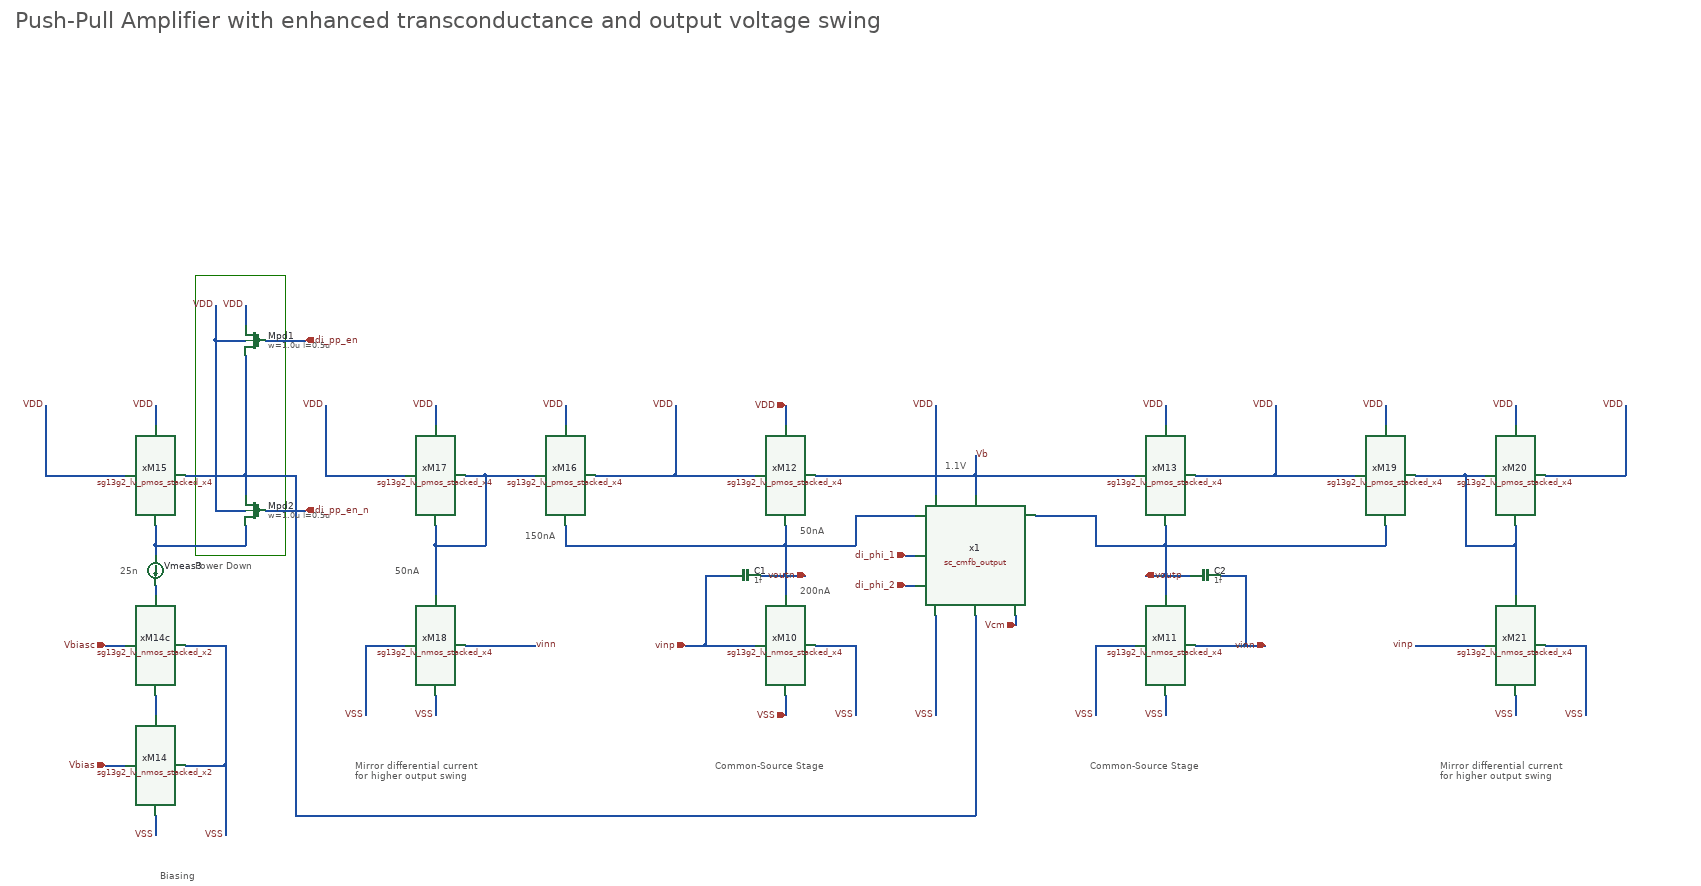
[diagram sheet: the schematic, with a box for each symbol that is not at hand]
v {xschem version=3.4.7 file_version=1.2}
G {}
K {}
V {}
S {}
E {}
P 4 5 540 -1280 540 -1840 720 -1840 720 -1280 540 -1280 {dash = 8}
T {Push-Pull Amplifier with enhanced transconductance and output voltage swing} 180 -2360 0 0 1.5 1.5 {}
T {200nA} 1750 -1220 0 0 0.4 0.4 {}
T {Common-Source Stage} 1580 -870 0 0 0.5 0.5 {}
T {Common-Source Stage} 2330 -870 0 0 0.5 0.5 {}
T {Mirror differential current
for higher output swing} 860 -870 0 0 0.5 0.5 {}
T {Mirror differential current
for higher output swing} 3030 -870 0 0 0.5 0.5 {}
T {50nA} 940 -1260 0 0 0.4 0.4 {}
T {150nA} 1200 -1330 0 0 0.4 0.4 {}
T {50nA} 1750 -1340 0 0 0.4 0.4 {}
T {25n} 390 -1260 0 0 0.4 0.4 {}
T {Power Down} 540 -1270 0 0 0.4 0.4 {}
T {Biasing} 470 -650 0 0 0.5 0.5 {}
T {1.1V} 2040 -1470 0 0 0.4 0.4 {}
N 1720 -1580 1720 -1540 {lab=VDD}
N 1860 -1100 1860 -960 {lab=VSS}
N 2640 -1100 2680 -1100 {lab=vinn}
N 2480 -1580 2480 -1540 {lab=VDD}
N 2540 -1100 2640 -1100 {lab=vinn}
N 2340 -1100 2340 -960 {lab=VSS}
N 2480 -1240 2480 -1200 {lab=voutp}
N 1500 -1580 1500 -1440 {lab=VDD}
N 2700 -1580 2700 -1440 {lab=VDD}
N 1500 -1440 1660 -1440 {lab=VDD}
N 2540 -1440 2700 -1440 {lab=VDD}
N 2480 -1300 2480 -1240 {lab=voutp}
N 1340 -1440 1500 -1440 {lab=VDD}
N 2480 -1340 2480 -1300 {lab=voutp}
N 1280 -1580 1280 -1540 {lab=VDD}
N 800 -1440 960 -1440 {lab=VDD}
N 1020 -1580 1020 -1540 {lab=VDD}
N 1080 -1100 1220 -1100 {lab=vinn}
N 1020 -1000 1020 -960 {lab=VSS}
N 1780 -1100 1860 -1100 {lab=VSS}
N 1720 -1000 1720 -960 {lab=VSS}
N 1560 -1100 1660 -1100 {lab=vinp}
N 2480 -1000 2480 -960 {lab=VSS}
N 2340 -1100 2420 -1100 {lab=VSS}
N 2640 -1240 2640 -1100 {lab=vinn}
N 1280 -1340 1280 -1300 {lab=voutn}
N 1720 -1340 1720 -1300 {lab=voutn}
N 2590 -1240 2640 -1240 {lab=vinn}
N 2480 -1240 2530 -1240 {lab=voutp}
N 1670 -1240 1720 -1240 {lab=voutn}
N 1560 -1240 1610 -1240 {lab=vinp}
N 1560 -1240 1560 -1100 {lab=vinp}
N 1520 -1100 1560 -1100 {lab=vinp}
N 1720 -1240 1720 -1200 {lab=voutn}
N 1120 -1440 1220 -1440 {lab=#net1}
N 1020 -1300 1120 -1300 {lab=#net1}
N 1020 -1340 1020 -1300 {lab=#net1}
N 1120 -1440 1120 -1300 {lab=#net1}
N 1080 -1440 1120 -1440 {lab=#net1}
N 2920 -1580 2920 -1540 {lab=VDD}
N 3240 -1440 3400 -1440 {lab=VDD}
N 3400 -1580 3400 -1440 {lab=VDD}
N 3180 -1580 3180 -1540 {lab=VDD}
N 2980 -1100 3120 -1100 {lab=vinp}
N 3180 -1300 3180 -1200 {lab=#net2}
N 3240 -1100 3320 -1100 {lab=VSS}
N 3320 -1100 3320 -960 {lab=VSS}
N 3180 -1000 3180 -960 {lab=VSS}
N 2920 -1340 2920 -1300 {lab=voutp}
N 2980 -1440 3080 -1440 {lab=#net2}
N 3080 -1300 3180 -1300 {lab=#net2}
N 3180 -1340 3180 -1300 {lab=#net2}
N 3080 -1440 3080 -1300 {lab=#net2}
N 3080 -1440 3120 -1440 {lab=#net2}
N 2700 -1440 2860 -1440 {lab=VDD}
N 1020 -1300 1020 -1200 {lab=#net1}
N 2480 -1300 2920 -1300 {lab=voutp}
N 1720 -1300 1860 -1300 {lab=voutn}
N 2340 -1300 2480 -1300 {lab=voutp}
N 2440 -1240 2480 -1240 {lab=voutp}
N 1720 -1240 1760 -1240 {lab=voutn}
N 1280 -1300 1720 -1300 {lab=voutn}
N 2100 -1440 2420 -1440 {lab=Vb}
N 2020 -1580 2020 -1400 {lab=VDD}
N 2100 -1440 2100 -1400 {lab=Vb}
N 1780 -1440 2100 -1440 {lab=Vb}
N 1860 -1360 1980 -1360 {lab=voutn}
N 1860 -1360 1860 -1300 {lab=voutn}
N 2220 -1360 2340 -1360 {lab=voutp}
N 2340 -1360 2340 -1300 {lab=voutp}
N 2100 -1160 2100 -760 {lab=#net3}
N 2020 -1160 2020 -960 {lab=VSS}
N 1960 -1280 1980 -1280 {lab=di_phi_1}
N 1960 -1220 1980 -1220 {lab=di_phi_2}
N 2180 -1160 2180 -1140 {lab=Vcm}
N 1720 -1300 1720 -1240 {lab=voutn}
N 2100 -1480 2100 -1440 {lab=Vb}
N 240 -1580 240 -1440 {lab=VDD}
N 240 -1440 400 -1440 {lab=VDD}
N 460 -1580 460 -1540 {lab=VDD}
N 460 -1300 460 -1280 {lab=#net4}
N 460 -1220 460 -1200 {lab=#net5}
N 880 -1100 880 -960 {lab=VSS}
N 640 -1780 640 -1740 {lab=VDD}
N 640 -1440 640 -1400 {lab=#net3}
N 640 -1340 640 -1300 {lab=#net4}
N 520 -1440 640 -1440 {lab=#net3}
N 640 -1680 640 -1440 {lab=#net3}
N 680 -1710 760 -1710 {lab=di_pp_en}
N 680 -1370 760 -1370 {lab=di_pp_en_n}
N 580 -1710 580 -1370 {lab=VDD}
N 580 -1370 640 -1370 {lab=VDD}
N 580 -1710 640 -1710 {lab=VDD}
N 580 -1780 580 -1710 {lab=VDD}
N 800 -1580 800 -1440 {lab=VDD}
N 460 -1300 640 -1300 {lab=#net4}
N 460 -1340 460 -1300 {lab=#net4}
N 640 -1440 740 -1440 {lab=#net3}
N 740 -1440 740 -760 {lab=#net3}
N 880 -1100 960 -1100 {lab=VSS}
N 740 -760 2100 -760 {lab=#net3}
N 520 -1100 600 -1100 {lab=VSS}
N 600 -860 600 -720 {lab=VSS}
N 460 -1000 460 -960 {lab=#net4}
N 460 -760 460 -720 {lab=VSS}
N 520 -860 600 -860 {lab=VSS}
N 600 -1100 600 -860 {lab=VSS}
N 360 -1100 400 -1100 {lab=Vbiasc}
N 360 -860 400 -860 {lab=Vbias}
C {title-2.sym} 0 0 0 0 {name=l2 author="Simon Dorrer" rev=1.0 lock=true}
C {stacked_transistors/sg13g2_lv_pmos_stacked/sg13g2_lv_pmos_stacked_x4.sym} 1720 -1440 0 1 {name=xM12 W_P=4.0u L_P=40.0u NG_P=8 M_P=1}
C {stacked_transistors/sg13g2_lv_nmos_stacked/sg13g2_lv_nmos_stacked_x4.sym} 1720 -1100 0 0 {name=xM10 W_N=2.0u L_N=40.0u NG_N=4 M_N=1}
C {ipin.sym} 1520 -1100 0 0 {name=p4 lab=vinp}
C {ipin.sym} 2680 -1100 2 0 {name=p6 lab=vinn}
C {opin.sym} 2440 -1240 2 0 {name=p3 lab=voutp}
C {opin.sym} 1760 -1240 2 1 {name=p7 lab=voutn}
C {devices/iopin.sym} 1720 -1580 3 0 {name=p34 lab=VDD}
C {devices/iopin.sym} 1720 -960 1 0 {name=p1 lab=VSS}
C {lab_pin.sym} 1860 -960 3 0 {name=p36 sig_type=std_logic lab=VSS}
C {lab_pin.sym} 2340 -960 1 1 {name=p12 sig_type=std_logic lab=VSS}
C {lab_pin.sym} 2480 -1580 3 1 {name=p5 sig_type=std_logic lab=VDD}
C {lab_pin.sym} 2480 -960 1 1 {name=p8 sig_type=std_logic lab=VSS}
C {stacked_transistors/sg13g2_lv_pmos_stacked/sg13g2_lv_pmos_stacked_x4.sym} 2480 -1440 0 0 {name=xM13 W_P=4.0u L_P=40.0u NG_P=8 M_P=1}
C {stacked_transistors/sg13g2_lv_nmos_stacked/sg13g2_lv_nmos_stacked_x4.sym} 2480 -1100 0 1 {name=xM11 W_N=2.0u L_N=40.0u NG_N=4 M_N=1}
C {lab_pin.sym} 2700 -1580 3 1 {name=p9 sig_type=std_logic lab=VDD}
C {stacked_transistors/sg13g2_lv_pmos_stacked/sg13g2_lv_pmos_stacked_x4.sym} 1280 -1440 0 0 {name=xM16 W_P=3.0u L_P=40.0u NG_P=6 M_P=1}
C {lab_pin.sym} 1280 -1580 3 1 {name=p15 sig_type=std_logic lab=VDD}
C {lab_pin.sym} 1500 -1580 3 1 {name=p10 sig_type=std_logic lab=VDD}
C {stacked_transistors/sg13g2_lv_pmos_stacked/sg13g2_lv_pmos_stacked_x4.sym} 1020 -1440 0 1 {name=xM17 W_P=1.0u L_P=40.0u NG_P=2 M_P=1}
C {stacked_transistors/sg13g2_lv_nmos_stacked/sg13g2_lv_nmos_stacked_x4.sym} 1020 -1100 0 1 {name=xM18 W_N=0.5u L_N=40.0u NG_N=1 M_N=1}
C {lab_pin.sym} 1020 -1580 3 1 {name=p16 sig_type=std_logic lab=VDD}
C {lab_pin.sym} 1020 -960 3 0 {name=p17 sig_type=std_logic lab=VSS}
C {lab_pin.sym} 1220 -1100 0 1 {name=p19 sig_type=std_logic lab=vinn}
C {stacked_transistors/sg13g2_lv_pmos_stacked/sg13g2_lv_pmos_stacked_x4.sym} 2920 -1440 0 1 {name=xM19 W_P=3.0u L_P=40.0u NG_P=6 M_P=1}
C {lab_pin.sym} 2920 -1580 1 0 {name=p20 sig_type=std_logic lab=VDD}
C {stacked_transistors/sg13g2_lv_pmos_stacked/sg13g2_lv_pmos_stacked_x4.sym} 3180 -1440 0 0 {name=xM20 W_P=1.0u L_P=40.0u NG_P=2 M_P=1}
C {stacked_transistors/sg13g2_lv_nmos_stacked/sg13g2_lv_nmos_stacked_x4.sym} 3180 -1100 0 0 {name=xM21 W_N=0.5u L_N=40.0u NG_N=1 M_N=1}
C {lab_pin.sym} 3400 -1580 1 0 {name=p21 sig_type=std_logic lab=VDD}
C {lab_pin.sym} 3180 -1580 1 0 {name=p22 sig_type=std_logic lab=VDD}
C {lab_pin.sym} 3180 -960 1 1 {name=p23 sig_type=std_logic lab=VSS}
C {lab_pin.sym} 2980 -1100 0 0 {name=p24 sig_type=std_logic lab=vinp}
C {lab_pin.sym} 3320 -960 1 1 {name=p25 sig_type=std_logic lab=VSS}
C {bio_amplifier/amplifier_core/sc_cmfb/sc_cmfb_output.sym} 2100 -1280 0 0 {name=x1 W_P_CMFB=2.0u L_P_CMFB=0.5u W_N_CMFB=2.0u L_N_CMFB=0.5u W_P_CMFB_D=1.0u W_N_CMFB_D=1.0u C1=100f a=9}
C {lab_pin.sym} 2020 -1580 3 1 {name=p26 sig_type=std_logic lab=VDD}
C {lab_pin.sym} 2020 -960 3 0 {name=p27 sig_type=std_logic lab=VSS}
C {ipin.sym} 1960 -1280 0 0 {name=p28 lab=di_phi_1}
C {ipin.sym} 1960 -1220 0 0 {name=p29 lab=di_phi_2}
C {ipin.sym} 2180 -1140 3 0 {name=p30 lab=Vcm}
C {lab_pin.sym} 2100 -1480 0 1 {name=p31 sig_type=std_logic lab=Vb}
C {lab_pin.sym} 240 -1580 3 1 {name=p13 sig_type=std_logic lab=VDD}
C {lab_pin.sym} 460 -1580 3 1 {name=p14 sig_type=std_logic lab=VDD}
C {stacked_transistors/sg13g2_lv_pmos_stacked/sg13g2_lv_pmos_stacked_x4.sym} 460 -1440 0 1 {name=xM15 W_P=2.0u L_P=40.0u NG_P=4 M_P=1}
C {lab_pin.sym} 880 -960 1 1 {name=p33 sig_type=std_logic lab=VSS}
C {ammeter.sym} 460 -1250 0 0 {name=Vmeas3 savecurrent=true spice_ignore=0}
C {lab_pin.sym} 800 -1580 3 1 {name=p18 sig_type=std_logic lab=VDD}
C {sg13g2_pr/sg13_hv_pmos.sym} 660 -1370 0 1 {name=Mpd2
l=0.5u
w=1.0u
ng=1
m=1
model=sg13_hv_pmos
spiceprefix=X
}
C {sg13g2_pr/sg13_hv_pmos.sym} 660 -1710 0 1 {name=Mpd1
l=0.5u
w=1.0u
ng=1
m=1
model=sg13_hv_pmos
spiceprefix=X
}
C {lab_pin.sym} 580 -1780 3 1 {name=p38 sig_type=std_logic lab=VDD}
C {lab_pin.sym} 640 -1780 3 1 {name=p39 sig_type=std_logic lab=VDD}
C {ipin.sym} 760 -1710 0 1 {name=p40 lab=di_pp_en}
C {ipin.sym} 760 -1370 0 1 {name=p41 lab=di_pp_en_n}
C {devices/capa.sym} 1640 -1240 1 0 {name=C1
m=1
value=1f
footprint=1206
device="ceramic capacitor"
spice_ignore=True}
C {devices/capa.sym} 2560 -1240 1 0 {name=C2
m=1
value=1f
footprint=1206
device="ceramic capacitor"
spice_ignore=True}
C {stacked_transistors/sg13g2_lv_nmos_stacked/sg13g2_lv_nmos_stacked_x2.sym} 460 -1100 0 0 {name=xM14c W_N=11.5u L_N=20.0u NG_N=23 M_N=1}
C {lab_pin.sym} 460 -720 1 1 {name=p2 sig_type=std_logic lab=VSS}
C {lab_pin.sym} 600 -720 1 1 {name=p35 sig_type=std_logic lab=VSS}
C {ipin.sym} 360 -860 0 0 {name=p11 lab=Vbias}
C {ipin.sym} 360 -1100 0 0 {name=p32 lab=Vbiasc}
C {stacked_transistors/sg13g2_lv_nmos_stacked/sg13g2_lv_nmos_stacked_x2.sym} 460 -860 0 0 {name=xM14 W_N=11.5u L_N=20.0u NG_N=23 M_N=1}
